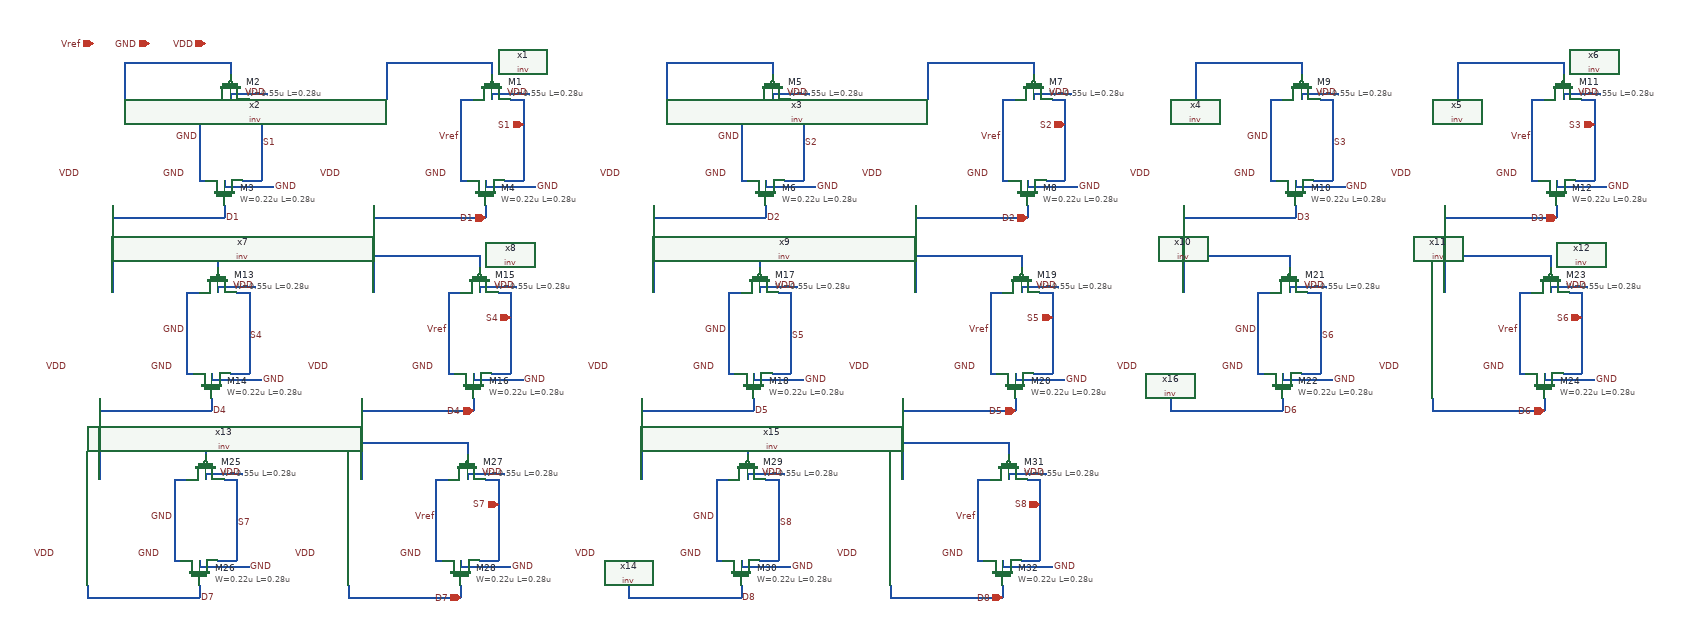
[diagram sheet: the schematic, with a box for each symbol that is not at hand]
v {xschem version=3.4.8RC file_version=1.2}
G {}
K {}
V {}
S {}
E {}
N 310 20 480 20 {lab=D1}
N 480 0 480 20 {lab=D1}
N 520 -170 540 -170 {lab=S1}
N 540 -170 540 -40 {lab=S1}
N 510 -40 540 -40 {lab=S1}
N 440 -170 460 -170 {lab=GND}
N 440 -170 440 -40 {lab=GND}
N 440 -40 450 -40 {lab=GND}
N 320 -230 320 -170 {lab=#net1}
N 320 -230 490 -230 {lab=#net1}
N 490 -230 490 -210 {lab=#net1}
N 490 -180 490 -170 {lab=VDD}
N 490 -180 550 -180 {lab=VDD}
N 480 -40 480 -30 {lab=GND}
N 480 -30 560 -30 {lab=GND}
N 300 0 300 20 {lab=D1}
N 300 20 310 20 {lab=D1}
N 730 20 900 20 {lab=D1}
N 900 0 900 20 {lab=D1}
N 940 -170 960 -170 {lab=S1}
N 960 -170 960 -40 {lab=S1}
N 930 -40 960 -40 {lab=S1}
N 860 -170 880 -170 {lab=Vref}
N 860 -170 860 -40 {lab=Vref}
N 860 -40 870 -40 {lab=Vref}
N 740 -230 740 -170 {lab=#net2}
N 740 -230 910 -230 {lab=#net2}
N 910 -230 910 -210 {lab=#net2}
N 910 -180 910 -170 {lab=VDD}
N 910 -180 970 -180 {lab=VDD}
N 900 -40 900 -30 {lab=GND}
N 900 -30 980 -30 {lab=GND}
N 720 0 720 20 {lab=D1}
N 720 20 730 20 {lab=D1}
N 1180 20 1350 20 {lab=D2}
N 1350 0 1350 20 {lab=D2}
N 1390 -170 1410 -170 {lab=S2}
N 1410 -170 1410 -40 {lab=S2}
N 1380 -40 1410 -40 {lab=S2}
N 1310 -170 1330 -170 {lab=GND}
N 1310 -170 1310 -40 {lab=GND}
N 1310 -40 1320 -40 {lab=GND}
N 1190 -230 1190 -170 {lab=#net3}
N 1190 -230 1360 -230 {lab=#net3}
N 1360 -230 1360 -210 {lab=#net3}
N 1360 -180 1360 -170 {lab=VDD}
N 1360 -180 1420 -180 {lab=VDD}
N 1350 -40 1350 -30 {lab=GND}
N 1350 -30 1430 -30 {lab=GND}
N 1170 0 1170 20 {lab=D2}
N 1170 20 1180 20 {lab=D2}
N 1600 20 1770 20 {lab=D2}
N 1770 0 1770 20 {lab=D2}
N 1810 -170 1830 -170 {lab=S2}
N 1830 -170 1830 -40 {lab=S2}
N 1800 -40 1830 -40 {lab=S2}
N 1730 -170 1750 -170 {lab=Vref}
N 1730 -170 1730 -40 {lab=Vref}
N 1730 -40 1740 -40 {lab=Vref}
N 1610 -230 1610 -170 {lab=#net4}
N 1610 -230 1780 -230 {lab=#net4}
N 1780 -230 1780 -210 {lab=#net4}
N 1780 -180 1780 -170 {lab=VDD}
N 1780 -180 1840 -180 {lab=VDD}
N 1770 -40 1770 -30 {lab=GND}
N 1770 -30 1850 -30 {lab=GND}
N 1590 0 1590 20 {lab=D2}
N 1590 20 1600 20 {lab=D2}
N 2030 20 2200 20 {lab=D3}
N 2200 0 2200 20 {lab=D3}
N 2240 -170 2260 -170 {lab=S3}
N 2260 -170 2260 -40 {lab=S3}
N 2230 -40 2260 -40 {lab=S3}
N 2160 -170 2180 -170 {lab=GND}
N 2160 -170 2160 -40 {lab=GND}
N 2160 -40 2170 -40 {lab=GND}
N 2040 -230 2040 -170 {lab=#net5}
N 2040 -230 2210 -230 {lab=#net5}
N 2210 -230 2210 -210 {lab=#net5}
N 2210 -180 2210 -170 {lab=VDD}
N 2210 -180 2270 -180 {lab=VDD}
N 2200 -40 2200 -30 {lab=GND}
N 2200 -30 2280 -30 {lab=GND}
N 2020 0 2020 20 {lab=D3}
N 2020 20 2030 20 {lab=D3}
N 2450 20 2620 20 {lab=D3}
N 2620 0 2620 20 {lab=D3}
N 2660 -170 2680 -170 {lab=S3}
N 2680 -170 2680 -40 {lab=S3}
N 2650 -40 2680 -40 {lab=S3}
N 2580 -170 2600 -170 {lab=Vref}
N 2580 -170 2580 -40 {lab=Vref}
N 2580 -40 2590 -40 {lab=Vref}
N 2460 -230 2460 -170 {lab=#net6}
N 2460 -230 2630 -230 {lab=#net6}
N 2630 -230 2630 -210 {lab=#net6}
N 2630 -180 2630 -170 {lab=VDD}
N 2630 -180 2690 -180 {lab=VDD}
N 2620 -40 2620 -30 {lab=GND}
N 2620 -30 2700 -30 {lab=GND}
N 2440 0 2440 20 {lab=D3}
N 2440 20 2450 20 {lab=D3}
N 290 330 460 330 {lab=D4}
N 460 310 460 330 {lab=D4}
N 500 140 520 140 {lab=S4}
N 520 140 520 270 {lab=S4}
N 490 270 520 270 {lab=S4}
N 420 140 440 140 {lab=GND}
N 420 140 420 270 {lab=GND}
N 420 270 430 270 {lab=GND}
N 300 80 300 140 {lab=#net7}
N 300 80 470 80 {lab=#net7}
N 470 80 470 100 {lab=#net7}
N 470 130 470 140 {lab=VDD}
N 470 130 530 130 {lab=VDD}
N 460 270 460 280 {lab=GND}
N 460 280 540 280 {lab=GND}
N 280 310 280 330 {lab=D4}
N 280 330 290 330 {lab=D4}
N 710 330 880 330 {lab=D4}
N 880 310 880 330 {lab=D4}
N 920 140 940 140 {lab=S4}
N 940 140 940 270 {lab=S4}
N 910 270 940 270 {lab=S4}
N 840 140 860 140 {lab=Vref}
N 840 140 840 270 {lab=Vref}
N 840 270 850 270 {lab=Vref}
N 720 80 720 140 {lab=#net8}
N 720 80 890 80 {lab=#net8}
N 890 80 890 100 {lab=#net8}
N 890 130 890 140 {lab=VDD}
N 890 130 950 130 {lab=VDD}
N 880 270 880 280 {lab=GND}
N 880 280 960 280 {lab=GND}
N 700 310 700 330 {lab=D4}
N 700 330 710 330 {lab=D4}
N 1160 330 1330 330 {lab=D5}
N 1330 310 1330 330 {lab=D5}
N 1370 140 1390 140 {lab=S5}
N 1390 140 1390 270 {lab=S5}
N 1360 270 1390 270 {lab=S5}
N 1290 140 1310 140 {lab=GND}
N 1290 140 1290 270 {lab=GND}
N 1290 270 1300 270 {lab=GND}
N 1170 80 1170 140 {lab=#net9}
N 1170 80 1340 80 {lab=#net9}
N 1340 80 1340 100 {lab=#net9}
N 1340 130 1340 140 {lab=VDD}
N 1340 130 1400 130 {lab=VDD}
N 1330 270 1330 280 {lab=GND}
N 1330 280 1410 280 {lab=GND}
N 1150 310 1150 330 {lab=D5}
N 1150 330 1160 330 {lab=D5}
N 1580 330 1750 330 {lab=D5}
N 1750 310 1750 330 {lab=D5}
N 1790 140 1810 140 {lab=S5}
N 1810 140 1810 270 {lab=S5}
N 1780 270 1810 270 {lab=S5}
N 1710 140 1730 140 {lab=Vref}
N 1710 140 1710 270 {lab=Vref}
N 1710 270 1720 270 {lab=Vref}
N 1590 80 1590 140 {lab=#net10}
N 1590 80 1760 80 {lab=#net10}
N 1760 80 1760 100 {lab=#net10}
N 1760 130 1760 140 {lab=VDD}
N 1760 130 1820 130 {lab=VDD}
N 1750 270 1750 280 {lab=GND}
N 1750 280 1830 280 {lab=GND}
N 1570 310 1570 330 {lab=D5}
N 1570 330 1580 330 {lab=D5}
N 2010 330 2180 330 {lab=D6}
N 2180 310 2180 330 {lab=D6}
N 2220 140 2240 140 {lab=S6}
N 2240 140 2240 270 {lab=S6}
N 2210 270 2240 270 {lab=S6}
N 2140 140 2160 140 {lab=GND}
N 2140 140 2140 270 {lab=GND}
N 2140 270 2150 270 {lab=GND}
N 2020 80 2020 140 {lab=#net11}
N 2020 80 2190 80 {lab=#net11}
N 2190 80 2190 100 {lab=#net11}
N 2190 130 2190 140 {lab=VDD}
N 2190 130 2250 130 {lab=VDD}
N 2180 270 2180 280 {lab=GND}
N 2180 280 2260 280 {lab=GND}
N 2000 310 2000 330 {lab=D6}
N 2000 330 2010 330 {lab=D6}
N 2430 330 2600 330 {lab=D3}
N 2600 310 2600 330 {lab=D3}
N 2640 140 2660 140 {lab=S6}
N 2660 140 2660 270 {lab=S6}
N 2630 270 2660 270 {lab=S6}
N 2560 140 2580 140 {lab=Vref}
N 2560 140 2560 270 {lab=Vref}
N 2560 270 2570 270 {lab=Vref}
N 2440 80 2440 140 {lab=#net12}
N 2440 80 2610 80 {lab=#net12}
N 2610 80 2610 100 {lab=#net12}
N 2610 130 2610 140 {lab=VDD}
N 2610 130 2670 130 {lab=VDD}
N 2600 270 2600 280 {lab=GND}
N 2600 280 2680 280 {lab=GND}
N 2420 310 2420 330 {lab=D3}
N 2420 330 2430 330 {lab=D3}
N 270 630 440 630 {lab=D4}
N 440 610 440 630 {lab=D4}
N 480 440 500 440 {lab=S4}
N 500 440 500 570 {lab=S4}
N 470 570 500 570 {lab=S4}
N 400 440 420 440 {lab=GND}
N 400 440 400 570 {lab=GND}
N 400 570 410 570 {lab=GND}
N 280 380 280 440 {lab=#net7}
N 280 380 450 380 {lab=#net7}
N 450 380 450 400 {lab=#net7}
N 450 430 450 440 {lab=VDD}
N 450 430 510 430 {lab=VDD}
N 440 570 440 580 {lab=GND}
N 440 580 520 580 {lab=GND}
N 260 610 260 630 {lab=D4}
N 260 630 270 630 {lab=D4}
N 690 630 860 630 {lab=D4}
N 860 610 860 630 {lab=D4}
N 900 440 920 440 {lab=S4}
N 920 440 920 570 {lab=S4}
N 890 570 920 570 {lab=S4}
N 820 440 840 440 {lab=Vref}
N 820 440 820 570 {lab=Vref}
N 820 570 830 570 {lab=Vref}
N 700 380 700 440 {lab=#net8}
N 700 380 870 380 {lab=#net8}
N 870 380 870 400 {lab=#net8}
N 870 430 870 440 {lab=VDD}
N 870 430 930 430 {lab=VDD}
N 860 570 860 580 {lab=GND}
N 860 580 940 580 {lab=GND}
N 680 610 680 630 {lab=D4}
N 680 630 690 630 {lab=D4}
N 1140 630 1310 630 {lab=D5}
N 1310 610 1310 630 {lab=D5}
N 1350 440 1370 440 {lab=S5}
N 1370 440 1370 570 {lab=S5}
N 1340 570 1370 570 {lab=S5}
N 1270 440 1290 440 {lab=GND}
N 1270 440 1270 570 {lab=GND}
N 1270 570 1280 570 {lab=GND}
N 1150 380 1150 440 {lab=#net9}
N 1150 380 1320 380 {lab=#net9}
N 1320 380 1320 400 {lab=#net9}
N 1320 430 1320 440 {lab=VDD}
N 1320 430 1380 430 {lab=VDD}
N 1310 570 1310 580 {lab=GND}
N 1310 580 1390 580 {lab=GND}
N 1130 610 1130 630 {lab=D5}
N 1130 630 1140 630 {lab=D5}
N 1560 630 1730 630 {lab=D5}
N 1730 610 1730 630 {lab=D5}
N 1770 440 1790 440 {lab=S5}
N 1790 440 1790 570 {lab=S5}
N 1760 570 1790 570 {lab=S5}
N 1690 440 1710 440 {lab=Vref}
N 1690 440 1690 570 {lab=Vref}
N 1690 570 1700 570 {lab=Vref}
N 1570 380 1570 440 {lab=#net10}
N 1570 380 1740 380 {lab=#net10}
N 1740 380 1740 400 {lab=#net10}
N 1740 430 1740 440 {lab=VDD}
N 1740 430 1800 430 {lab=VDD}
N 1730 570 1730 580 {lab=GND}
N 1730 580 1810 580 {lab=GND}
N 1550 610 1550 630 {lab=D5}
N 1550 630 1560 630 {lab=D5}
C {lab_wire.sym} 540 -100 0 1 {name=p1 sig_type=std_logic lab=S1}
C {lab_wire.sym} 440 -110 2 1 {name=p5 sig_type=std_logic lab=GND}
C {symbols/pfet_03v3.sym} 490 -190 3 1 {name=M2
L=0.28u
W=0.55u
nf=1
m=1
ad="'int((nf+1)/2) * W/nf * 0.18u'"
pd="'2*int((nf+1)/2) * (W/nf + 0.18u)'"
as="'int((nf+2)/2) * W/nf * 0.18u'"
ps="'2*int((nf+2)/2) * (W/nf + 0.18u)'"
nrd="'0.18u / W'" nrs="'0.18u / W'"
sa=0 sb=0 sd=0
model=pfet_03v3
spiceprefix=X
}
C {symbols/nfet_03v3.sym} 480 -20 1 1 {name=M3
L=0.28u
W=0.22u
nf=1
m=1
ad="'int((nf+1)/2) * W/nf * 0.18u'"
pd="'2*int((nf+1)/2) * (W/nf + 0.18u)'"
as="'int((nf+2)/2) * W/nf * 0.18u'"
ps="'2*int((nf+2)/2) * (W/nf + 0.18u)'"
nrd="'0.18u / W'" nrs="'0.18u / W'"
sa=0 sb=0 sd=0
model=nfet_03v3
spiceprefix=X
}
C {lab_wire.sym} 560 -30 2 0 {name=p6 sig_type=std_logic lab=GND}
C {lab_wire.sym} 380 -50 2 0 {name=p7 sig_type=std_logic lab=GND}
C {lab_wire.sym} 250 -50 0 0 {name=p8 sig_type=std_logic lab=VDD}
C {lab_wire.sym} 550 -180 0 0 {name=p9 sig_type=std_logic lab=VDD}
C {iopin.sym} 450 -260 0 0 {name=p12 lab=VDD}
C {iopin.sym} 360 -260 0 0 {name=p13 lab=GND}
C {inv.sym} 540 -230 3 0 {name=x2}
C {iopin.sym} 270 -260 0 0 {name=p14 lab=Vref}
C {lab_wire.sym} 480 20 0 1 {name=p2 sig_type=std_logic lab=D1}
C {lab_wire.sym} 860 -110 2 1 {name=p4 sig_type=std_logic lab=Vref}
C {symbols/pfet_03v3.sym} 910 -190 3 1 {name=M1
L=0.28u
W=0.55u
nf=1
m=1
ad="'int((nf+1)/2) * W/nf * 0.18u'"
pd="'2*int((nf+1)/2) * (W/nf + 0.18u)'"
as="'int((nf+2)/2) * W/nf * 0.18u'"
ps="'2*int((nf+2)/2) * (W/nf + 0.18u)'"
nrd="'0.18u / W'" nrs="'0.18u / W'"
sa=0 sb=0 sd=0
model=pfet_03v3
spiceprefix=X
}
C {symbols/nfet_03v3.sym} 900 -20 1 1 {name=M4
L=0.28u
W=0.22u
nf=1
m=1
ad="'int((nf+1)/2) * W/nf * 0.18u'"
pd="'2*int((nf+1)/2) * (W/nf + 0.18u)'"
as="'int((nf+2)/2) * W/nf * 0.18u'"
ps="'2*int((nf+2)/2) * (W/nf + 0.18u)'"
nrd="'0.18u / W'" nrs="'0.18u / W'"
sa=0 sb=0 sd=0
model=nfet_03v3
spiceprefix=X
}
C {lab_wire.sym} 980 -30 2 0 {name=p10 sig_type=std_logic lab=GND}
C {lab_wire.sym} 800 -50 2 0 {name=p11 sig_type=std_logic lab=GND}
C {lab_wire.sym} 670 -50 0 0 {name=p15 sig_type=std_logic lab=VDD}
C {lab_wire.sym} 970 -180 0 0 {name=p16 sig_type=std_logic lab=VDD}
C {inv.sym} 960 -230 3 0 {name=x1}
C {iopin.sym} 960 -130 0 0 {name=p18 lab=S1}
C {iopin.sym} 900 20 0 0 {name=p3 lab=D1}
C {lab_wire.sym} 1410 -100 0 1 {name=p17 sig_type=std_logic lab=S2}
C {lab_wire.sym} 1310 -110 2 1 {name=p19 sig_type=std_logic lab=GND}
C {symbols/pfet_03v3.sym} 1360 -190 3 1 {name=M5
L=0.28u
W=0.55u
nf=1
m=1
ad="'int((nf+1)/2) * W/nf * 0.18u'"
pd="'2*int((nf+1)/2) * (W/nf + 0.18u)'"
as="'int((nf+2)/2) * W/nf * 0.18u'"
ps="'2*int((nf+2)/2) * (W/nf + 0.18u)'"
nrd="'0.18u / W'" nrs="'0.18u / W'"
sa=0 sb=0 sd=0
model=pfet_03v3
spiceprefix=X
}
C {symbols/nfet_03v3.sym} 1350 -20 1 1 {name=M6
L=0.28u
W=0.22u
nf=1
m=1
ad="'int((nf+1)/2) * W/nf * 0.18u'"
pd="'2*int((nf+1)/2) * (W/nf + 0.18u)'"
as="'int((nf+2)/2) * W/nf * 0.18u'"
ps="'2*int((nf+2)/2) * (W/nf + 0.18u)'"
nrd="'0.18u / W'" nrs="'0.18u / W'"
sa=0 sb=0 sd=0
model=nfet_03v3
spiceprefix=X
}
C {lab_wire.sym} 1430 -30 2 0 {name=p20 sig_type=std_logic lab=GND}
C {lab_wire.sym} 1250 -50 2 0 {name=p21 sig_type=std_logic lab=GND}
C {lab_wire.sym} 1120 -50 0 0 {name=p22 sig_type=std_logic lab=VDD}
C {lab_wire.sym} 1420 -180 0 0 {name=p23 sig_type=std_logic lab=VDD}
C {inv.sym} 1410 -230 3 0 {name=x3}
C {lab_wire.sym} 1350 20 0 1 {name=p24 sig_type=std_logic lab=D2}
C {lab_wire.sym} 1730 -110 2 1 {name=p25 sig_type=std_logic lab=Vref}
C {symbols/pfet_03v3.sym} 1780 -190 3 1 {name=M7
L=0.28u
W=0.55u
nf=1
m=1
ad="'int((nf+1)/2) * W/nf * 0.18u'"
pd="'2*int((nf+1)/2) * (W/nf + 0.18u)'"
as="'int((nf+2)/2) * W/nf * 0.18u'"
ps="'2*int((nf+2)/2) * (W/nf + 0.18u)'"
nrd="'0.18u / W'" nrs="'0.18u / W'"
sa=0 sb=0 sd=0
model=pfet_03v3
spiceprefix=X
}
C {symbols/nfet_03v3.sym} 1770 -20 1 1 {name=M8
L=0.28u
W=0.22u
nf=1
m=1
ad="'int((nf+1)/2) * W/nf * 0.18u'"
pd="'2*int((nf+1)/2) * (W/nf + 0.18u)'"
as="'int((nf+2)/2) * W/nf * 0.18u'"
ps="'2*int((nf+2)/2) * (W/nf + 0.18u)'"
nrd="'0.18u / W'" nrs="'0.18u / W'"
sa=0 sb=0 sd=0
model=nfet_03v3
spiceprefix=X
}
C {lab_wire.sym} 1850 -30 2 0 {name=p26 sig_type=std_logic lab=GND}
C {lab_wire.sym} 1670 -50 2 0 {name=p27 sig_type=std_logic lab=GND}
C {lab_wire.sym} 1540 -50 0 0 {name=p28 sig_type=std_logic lab=VDD}
C {lab_wire.sym} 1840 -180 0 0 {name=p29 sig_type=std_logic lab=VDD}
C {inv.sym} 1830 -230 3 0 {name=x4}
C {iopin.sym} 1830 -130 0 0 {name=p30 lab=S2}
C {iopin.sym} 1770 20 0 0 {name=p31 lab=D2}
C {lab_wire.sym} 2260 -100 0 1 {name=p32 sig_type=std_logic lab=S3}
C {lab_wire.sym} 2160 -110 2 1 {name=p33 sig_type=std_logic lab=GND}
C {symbols/pfet_03v3.sym} 2210 -190 3 1 {name=M9
L=0.28u
W=0.55u
nf=1
m=1
ad="'int((nf+1)/2) * W/nf * 0.18u'"
pd="'2*int((nf+1)/2) * (W/nf + 0.18u)'"
as="'int((nf+2)/2) * W/nf * 0.18u'"
ps="'2*int((nf+2)/2) * (W/nf + 0.18u)'"
nrd="'0.18u / W'" nrs="'0.18u / W'"
sa=0 sb=0 sd=0
model=pfet_03v3
spiceprefix=X
}
C {symbols/nfet_03v3.sym} 2200 -20 1 1 {name=M10
L=0.28u
W=0.22u
nf=1
m=1
ad="'int((nf+1)/2) * W/nf * 0.18u'"
pd="'2*int((nf+1)/2) * (W/nf + 0.18u)'"
as="'int((nf+2)/2) * W/nf * 0.18u'"
ps="'2*int((nf+2)/2) * (W/nf + 0.18u)'"
nrd="'0.18u / W'" nrs="'0.18u / W'"
sa=0 sb=0 sd=0
model=nfet_03v3
spiceprefix=X
}
C {lab_wire.sym} 2280 -30 2 0 {name=p34 sig_type=std_logic lab=GND}
C {lab_wire.sym} 2100 -50 2 0 {name=p35 sig_type=std_logic lab=GND}
C {lab_wire.sym} 1970 -50 0 0 {name=p36 sig_type=std_logic lab=VDD}
C {lab_wire.sym} 2270 -180 0 0 {name=p37 sig_type=std_logic lab=VDD}
C {inv.sym} 2260 -230 3 0 {name=x5}
C {lab_wire.sym} 2200 20 0 1 {name=p38 sig_type=std_logic lab=D3}
C {lab_wire.sym} 2580 -110 2 1 {name=p39 sig_type=std_logic lab=Vref}
C {symbols/pfet_03v3.sym} 2630 -190 3 1 {name=M11
L=0.28u
W=0.55u
nf=1
m=1
ad="'int((nf+1)/2) * W/nf * 0.18u'"
pd="'2*int((nf+1)/2) * (W/nf + 0.18u)'"
as="'int((nf+2)/2) * W/nf * 0.18u'"
ps="'2*int((nf+2)/2) * (W/nf + 0.18u)'"
nrd="'0.18u / W'" nrs="'0.18u / W'"
sa=0 sb=0 sd=0
model=pfet_03v3
spiceprefix=X
}
C {symbols/nfet_03v3.sym} 2620 -20 1 1 {name=M12
L=0.28u
W=0.22u
nf=1
m=1
ad="'int((nf+1)/2) * W/nf * 0.18u'"
pd="'2*int((nf+1)/2) * (W/nf + 0.18u)'"
as="'int((nf+2)/2) * W/nf * 0.18u'"
ps="'2*int((nf+2)/2) * (W/nf + 0.18u)'"
nrd="'0.18u / W'" nrs="'0.18u / W'"
sa=0 sb=0 sd=0
model=nfet_03v3
spiceprefix=X
}
C {lab_wire.sym} 2700 -30 2 0 {name=p40 sig_type=std_logic lab=GND}
C {lab_wire.sym} 2520 -50 2 0 {name=p41 sig_type=std_logic lab=GND}
C {lab_wire.sym} 2390 -50 0 0 {name=p42 sig_type=std_logic lab=VDD}
C {lab_wire.sym} 2690 -180 0 0 {name=p43 sig_type=std_logic lab=VDD}
C {inv.sym} 2680 -230 3 0 {name=x6}
C {iopin.sym} 2680 -130 0 0 {name=p44 lab=S3}
C {iopin.sym} 2620 20 0 0 {name=p45 lab=D3}
C {lab_wire.sym} 520 210 0 1 {name=p46 sig_type=std_logic lab=S4}
C {lab_wire.sym} 420 200 2 1 {name=p47 sig_type=std_logic lab=GND}
C {symbols/pfet_03v3.sym} 470 120 3 1 {name=M13
L=0.28u
W=0.55u
nf=1
m=1
ad="'int((nf+1)/2) * W/nf * 0.18u'"
pd="'2*int((nf+1)/2) * (W/nf + 0.18u)'"
as="'int((nf+2)/2) * W/nf * 0.18u'"
ps="'2*int((nf+2)/2) * (W/nf + 0.18u)'"
nrd="'0.18u / W'" nrs="'0.18u / W'"
sa=0 sb=0 sd=0
model=pfet_03v3
spiceprefix=X
}
C {symbols/nfet_03v3.sym} 460 290 1 1 {name=M14
L=0.28u
W=0.22u
nf=1
m=1
ad="'int((nf+1)/2) * W/nf * 0.18u'"
pd="'2*int((nf+1)/2) * (W/nf + 0.18u)'"
as="'int((nf+2)/2) * W/nf * 0.18u'"
ps="'2*int((nf+2)/2) * (W/nf + 0.18u)'"
nrd="'0.18u / W'" nrs="'0.18u / W'"
sa=0 sb=0 sd=0
model=nfet_03v3
spiceprefix=X
}
C {lab_wire.sym} 540 280 2 0 {name=p48 sig_type=std_logic lab=GND}
C {lab_wire.sym} 360 260 2 0 {name=p49 sig_type=std_logic lab=GND}
C {lab_wire.sym} 230 260 0 0 {name=p50 sig_type=std_logic lab=VDD}
C {lab_wire.sym} 530 130 0 0 {name=p51 sig_type=std_logic lab=VDD}
C {inv.sym} 520 80 3 0 {name=x7}
C {lab_wire.sym} 460 330 0 1 {name=p52 sig_type=std_logic lab=D4}
C {lab_wire.sym} 840 200 2 1 {name=p53 sig_type=std_logic lab=Vref}
C {symbols/pfet_03v3.sym} 890 120 3 1 {name=M15
L=0.28u
W=0.55u
nf=1
m=1
ad="'int((nf+1)/2) * W/nf * 0.18u'"
pd="'2*int((nf+1)/2) * (W/nf + 0.18u)'"
as="'int((nf+2)/2) * W/nf * 0.18u'"
ps="'2*int((nf+2)/2) * (W/nf + 0.18u)'"
nrd="'0.18u / W'" nrs="'0.18u / W'"
sa=0 sb=0 sd=0
model=pfet_03v3
spiceprefix=X
}
C {symbols/nfet_03v3.sym} 880 290 1 1 {name=M16
L=0.28u
W=0.22u
nf=1
m=1
ad="'int((nf+1)/2) * W/nf * 0.18u'"
pd="'2*int((nf+1)/2) * (W/nf + 0.18u)'"
as="'int((nf+2)/2) * W/nf * 0.18u'"
ps="'2*int((nf+2)/2) * (W/nf + 0.18u)'"
nrd="'0.18u / W'" nrs="'0.18u / W'"
sa=0 sb=0 sd=0
model=nfet_03v3
spiceprefix=X
}
C {lab_wire.sym} 960 280 2 0 {name=p54 sig_type=std_logic lab=GND}
C {lab_wire.sym} 780 260 2 0 {name=p55 sig_type=std_logic lab=GND}
C {lab_wire.sym} 650 260 0 0 {name=p56 sig_type=std_logic lab=VDD}
C {lab_wire.sym} 950 130 0 0 {name=p57 sig_type=std_logic lab=VDD}
C {inv.sym} 940 80 3 0 {name=x8}
C {iopin.sym} 940 180 0 0 {name=p58 lab=S4}
C {iopin.sym} 880 330 0 0 {name=p59 lab=D4}
C {lab_wire.sym} 1390 210 0 1 {name=p60 sig_type=std_logic lab=S5}
C {lab_wire.sym} 1290 200 2 1 {name=p61 sig_type=std_logic lab=GND}
C {symbols/pfet_03v3.sym} 1340 120 3 1 {name=M17
L=0.28u
W=0.55u
nf=1
m=1
ad="'int((nf+1)/2) * W/nf * 0.18u'"
pd="'2*int((nf+1)/2) * (W/nf + 0.18u)'"
as="'int((nf+2)/2) * W/nf * 0.18u'"
ps="'2*int((nf+2)/2) * (W/nf + 0.18u)'"
nrd="'0.18u / W'" nrs="'0.18u / W'"
sa=0 sb=0 sd=0
model=pfet_03v3
spiceprefix=X
}
C {symbols/nfet_03v3.sym} 1330 290 1 1 {name=M18
L=0.28u
W=0.22u
nf=1
m=1
ad="'int((nf+1)/2) * W/nf * 0.18u'"
pd="'2*int((nf+1)/2) * (W/nf + 0.18u)'"
as="'int((nf+2)/2) * W/nf * 0.18u'"
ps="'2*int((nf+2)/2) * (W/nf + 0.18u)'"
nrd="'0.18u / W'" nrs="'0.18u / W'"
sa=0 sb=0 sd=0
model=nfet_03v3
spiceprefix=X
}
C {lab_wire.sym} 1410 280 2 0 {name=p62 sig_type=std_logic lab=GND}
C {lab_wire.sym} 1230 260 2 0 {name=p63 sig_type=std_logic lab=GND}
C {lab_wire.sym} 1100 260 0 0 {name=p64 sig_type=std_logic lab=VDD}
C {lab_wire.sym} 1400 130 0 0 {name=p65 sig_type=std_logic lab=VDD}
C {inv.sym} 1390 80 3 0 {name=x9}
C {lab_wire.sym} 1330 330 0 1 {name=p66 sig_type=std_logic lab=D5}
C {lab_wire.sym} 1710 200 2 1 {name=p67 sig_type=std_logic lab=Vref}
C {symbols/pfet_03v3.sym} 1760 120 3 1 {name=M19
L=0.28u
W=0.55u
nf=1
m=1
ad="'int((nf+1)/2) * W/nf * 0.18u'"
pd="'2*int((nf+1)/2) * (W/nf + 0.18u)'"
as="'int((nf+2)/2) * W/nf * 0.18u'"
ps="'2*int((nf+2)/2) * (W/nf + 0.18u)'"
nrd="'0.18u / W'" nrs="'0.18u / W'"
sa=0 sb=0 sd=0
model=pfet_03v3
spiceprefix=X
}
C {symbols/nfet_03v3.sym} 1750 290 1 1 {name=M20
L=0.28u
W=0.22u
nf=1
m=1
ad="'int((nf+1)/2) * W/nf * 0.18u'"
pd="'2*int((nf+1)/2) * (W/nf + 0.18u)'"
as="'int((nf+2)/2) * W/nf * 0.18u'"
ps="'2*int((nf+2)/2) * (W/nf + 0.18u)'"
nrd="'0.18u / W'" nrs="'0.18u / W'"
sa=0 sb=0 sd=0
model=nfet_03v3
spiceprefix=X
}
C {lab_wire.sym} 1830 280 2 0 {name=p68 sig_type=std_logic lab=GND}
C {lab_wire.sym} 1650 260 2 0 {name=p69 sig_type=std_logic lab=GND}
C {lab_wire.sym} 1520 260 0 0 {name=p70 sig_type=std_logic lab=VDD}
C {lab_wire.sym} 1820 130 0 0 {name=p71 sig_type=std_logic lab=VDD}
C {inv.sym} 1810 80 3 0 {name=x10}
C {iopin.sym} 1810 180 0 0 {name=p72 lab=S5}
C {iopin.sym} 1750 330 0 0 {name=p73 lab=D5}
C {lab_wire.sym} 2240 210 0 1 {name=p74 sig_type=std_logic lab=S6}
C {lab_wire.sym} 2140 200 2 1 {name=p75 sig_type=std_logic lab=GND}
C {symbols/pfet_03v3.sym} 2190 120 3 1 {name=M21
L=0.28u
W=0.55u
nf=1
m=1
ad="'int((nf+1)/2) * W/nf * 0.18u'"
pd="'2*int((nf+1)/2) * (W/nf + 0.18u)'"
as="'int((nf+2)/2) * W/nf * 0.18u'"
ps="'2*int((nf+2)/2) * (W/nf + 0.18u)'"
nrd="'0.18u / W'" nrs="'0.18u / W'"
sa=0 sb=0 sd=0
model=pfet_03v3
spiceprefix=X
}
C {symbols/nfet_03v3.sym} 2180 290 1 1 {name=M22
L=0.28u
W=0.22u
nf=1
m=1
ad="'int((nf+1)/2) * W/nf * 0.18u'"
pd="'2*int((nf+1)/2) * (W/nf + 0.18u)'"
as="'int((nf+2)/2) * W/nf * 0.18u'"
ps="'2*int((nf+2)/2) * (W/nf + 0.18u)'"
nrd="'0.18u / W'" nrs="'0.18u / W'"
sa=0 sb=0 sd=0
model=nfet_03v3
spiceprefix=X
}
C {lab_wire.sym} 2260 280 2 0 {name=p76 sig_type=std_logic lab=GND}
C {lab_wire.sym} 2080 260 2 0 {name=p77 sig_type=std_logic lab=GND}
C {lab_wire.sym} 1950 260 0 0 {name=p78 sig_type=std_logic lab=VDD}
C {lab_wire.sym} 2250 130 0 0 {name=p79 sig_type=std_logic lab=VDD}
C {inv.sym} 2240 80 3 0 {name=x11}
C {lab_wire.sym} 2180 330 0 1 {name=p80 sig_type=std_logic lab=D6}
C {lab_wire.sym} 2560 200 2 1 {name=p81 sig_type=std_logic lab=Vref}
C {symbols/pfet_03v3.sym} 2610 120 3 1 {name=M23
L=0.28u
W=0.55u
nf=1
m=1
ad="'int((nf+1)/2) * W/nf * 0.18u'"
pd="'2*int((nf+1)/2) * (W/nf + 0.18u)'"
as="'int((nf+2)/2) * W/nf * 0.18u'"
ps="'2*int((nf+2)/2) * (W/nf + 0.18u)'"
nrd="'0.18u / W'" nrs="'0.18u / W'"
sa=0 sb=0 sd=0
model=pfet_03v3
spiceprefix=X
}
C {symbols/nfet_03v3.sym} 2600 290 1 1 {name=M24
L=0.28u
W=0.22u
nf=1
m=1
ad="'int((nf+1)/2) * W/nf * 0.18u'"
pd="'2*int((nf+1)/2) * (W/nf + 0.18u)'"
as="'int((nf+2)/2) * W/nf * 0.18u'"
ps="'2*int((nf+2)/2) * (W/nf + 0.18u)'"
nrd="'0.18u / W'" nrs="'0.18u / W'"
sa=0 sb=0 sd=0
model=nfet_03v3
spiceprefix=X
}
C {lab_wire.sym} 2680 280 2 0 {name=p82 sig_type=std_logic lab=GND}
C {lab_wire.sym} 2500 260 2 0 {name=p83 sig_type=std_logic lab=GND}
C {lab_wire.sym} 2370 260 0 0 {name=p84 sig_type=std_logic lab=VDD}
C {lab_wire.sym} 2670 130 0 0 {name=p85 sig_type=std_logic lab=VDD}
C {inv.sym} 2660 80 3 0 {name=x12}
C {iopin.sym} 2660 180 0 0 {name=p86 lab=S6}
C {iopin.sym} 2600 330 0 0 {name=p87 lab=D6}
C {lab_wire.sym} 500 510 0 1 {name=p88 sig_type=std_logic lab=S7}
C {lab_wire.sym} 400 500 2 1 {name=p89 sig_type=std_logic lab=GND}
C {symbols/pfet_03v3.sym} 450 420 3 1 {name=M25
L=0.28u
W=0.55u
nf=1
m=1
ad="'int((nf+1)/2) * W/nf * 0.18u'"
pd="'2*int((nf+1)/2) * (W/nf + 0.18u)'"
as="'int((nf+2)/2) * W/nf * 0.18u'"
ps="'2*int((nf+2)/2) * (W/nf + 0.18u)'"
nrd="'0.18u / W'" nrs="'0.18u / W'"
sa=0 sb=0 sd=0
model=pfet_03v3
spiceprefix=X
}
C {symbols/nfet_03v3.sym} 440 590 1 1 {name=M26
L=0.28u
W=0.22u
nf=1
m=1
ad="'int((nf+1)/2) * W/nf * 0.18u'"
pd="'2*int((nf+1)/2) * (W/nf + 0.18u)'"
as="'int((nf+2)/2) * W/nf * 0.18u'"
ps="'2*int((nf+2)/2) * (W/nf + 0.18u)'"
nrd="'0.18u / W'" nrs="'0.18u / W'"
sa=0 sb=0 sd=0
model=nfet_03v3
spiceprefix=X
}
C {lab_wire.sym} 520 580 2 0 {name=p90 sig_type=std_logic lab=GND}
C {lab_wire.sym} 340 560 2 0 {name=p91 sig_type=std_logic lab=GND}
C {lab_wire.sym} 210 560 0 0 {name=p92 sig_type=std_logic lab=VDD}
C {lab_wire.sym} 510 430 0 0 {name=p93 sig_type=std_logic lab=VDD}
C {inv.sym} 500 380 3 0 {name=x13}
C {lab_wire.sym} 440 630 0 1 {name=p94 sig_type=std_logic lab=D7}
C {lab_wire.sym} 820 500 2 1 {name=p95 sig_type=std_logic lab=Vref}
C {symbols/pfet_03v3.sym} 870 420 3 1 {name=M27
L=0.28u
W=0.55u
nf=1
m=1
ad="'int((nf+1)/2) * W/nf * 0.18u'"
pd="'2*int((nf+1)/2) * (W/nf + 0.18u)'"
as="'int((nf+2)/2) * W/nf * 0.18u'"
ps="'2*int((nf+2)/2) * (W/nf + 0.18u)'"
nrd="'0.18u / W'" nrs="'0.18u / W'"
sa=0 sb=0 sd=0
model=pfet_03v3
spiceprefix=X
}
C {symbols/nfet_03v3.sym} 860 590 1 1 {name=M28
L=0.28u
W=0.22u
nf=1
m=1
ad="'int((nf+1)/2) * W/nf * 0.18u'"
pd="'2*int((nf+1)/2) * (W/nf + 0.18u)'"
as="'int((nf+2)/2) * W/nf * 0.18u'"
ps="'2*int((nf+2)/2) * (W/nf + 0.18u)'"
nrd="'0.18u / W'" nrs="'0.18u / W'"
sa=0 sb=0 sd=0
model=nfet_03v3
spiceprefix=X
}
C {lab_wire.sym} 940 580 2 0 {name=p96 sig_type=std_logic lab=GND}
C {lab_wire.sym} 760 560 2 0 {name=p97 sig_type=std_logic lab=GND}
C {lab_wire.sym} 630 560 0 0 {name=p98 sig_type=std_logic lab=VDD}
C {lab_wire.sym} 930 430 0 0 {name=p99 sig_type=std_logic lab=VDD}
C {inv.sym} 920 380 3 0 {name=x14}
C {iopin.sym} 920 480 0 0 {name=p100 lab=S7}
C {iopin.sym} 860 630 0 0 {name=p101 lab=D7}
C {lab_wire.sym} 1370 510 0 1 {name=p102 sig_type=std_logic lab=S8}
C {lab_wire.sym} 1270 500 2 1 {name=p103 sig_type=std_logic lab=GND}
C {symbols/pfet_03v3.sym} 1320 420 3 1 {name=M29
L=0.28u
W=0.55u
nf=1
m=1
ad="'int((nf+1)/2) * W/nf * 0.18u'"
pd="'2*int((nf+1)/2) * (W/nf + 0.18u)'"
as="'int((nf+2)/2) * W/nf * 0.18u'"
ps="'2*int((nf+2)/2) * (W/nf + 0.18u)'"
nrd="'0.18u / W'" nrs="'0.18u / W'"
sa=0 sb=0 sd=0
model=pfet_03v3
spiceprefix=X
}
C {symbols/nfet_03v3.sym} 1310 590 1 1 {name=M30
L=0.28u
W=0.22u
nf=1
m=1
ad="'int((nf+1)/2) * W/nf * 0.18u'"
pd="'2*int((nf+1)/2) * (W/nf + 0.18u)'"
as="'int((nf+2)/2) * W/nf * 0.18u'"
ps="'2*int((nf+2)/2) * (W/nf + 0.18u)'"
nrd="'0.18u / W'" nrs="'0.18u / W'"
sa=0 sb=0 sd=0
model=nfet_03v3
spiceprefix=X
}
C {lab_wire.sym} 1390 580 2 0 {name=p104 sig_type=std_logic lab=GND}
C {lab_wire.sym} 1210 560 2 0 {name=p105 sig_type=std_logic lab=GND}
C {lab_wire.sym} 1080 560 0 0 {name=p106 sig_type=std_logic lab=VDD}
C {lab_wire.sym} 1380 430 0 0 {name=p107 sig_type=std_logic lab=VDD}
C {inv.sym} 1370 380 3 0 {name=x15}
C {lab_wire.sym} 1310 630 0 1 {name=p108 sig_type=std_logic lab=D8}
C {lab_wire.sym} 1690 500 2 1 {name=p109 sig_type=std_logic lab=Vref}
C {symbols/pfet_03v3.sym} 1740 420 3 1 {name=M31
L=0.28u
W=0.55u
nf=1
m=1
ad="'int((nf+1)/2) * W/nf * 0.18u'"
pd="'2*int((nf+1)/2) * (W/nf + 0.18u)'"
as="'int((nf+2)/2) * W/nf * 0.18u'"
ps="'2*int((nf+2)/2) * (W/nf + 0.18u)'"
nrd="'0.18u / W'" nrs="'0.18u / W'"
sa=0 sb=0 sd=0
model=pfet_03v3
spiceprefix=X
}
C {symbols/nfet_03v3.sym} 1730 590 1 1 {name=M32
L=0.28u
W=0.22u
nf=1
m=1
ad="'int((nf+1)/2) * W/nf * 0.18u'"
pd="'2*int((nf+1)/2) * (W/nf + 0.18u)'"
as="'int((nf+2)/2) * W/nf * 0.18u'"
ps="'2*int((nf+2)/2) * (W/nf + 0.18u)'"
nrd="'0.18u / W'" nrs="'0.18u / W'"
sa=0 sb=0 sd=0
model=nfet_03v3
spiceprefix=X
}
C {lab_wire.sym} 1810 580 2 0 {name=p110 sig_type=std_logic lab=GND}
C {lab_wire.sym} 1630 560 2 0 {name=p111 sig_type=std_logic lab=GND}
C {lab_wire.sym} 1500 560 0 0 {name=p112 sig_type=std_logic lab=VDD}
C {lab_wire.sym} 1800 430 0 0 {name=p113 sig_type=std_logic lab=VDD}
C {inv.sym} 1790 380 3 0 {name=x16}
C {iopin.sym} 1790 480 0 0 {name=p114 lab=S8}
C {iopin.sym} 1730 630 0 0 {name=p115 lab=D8}
